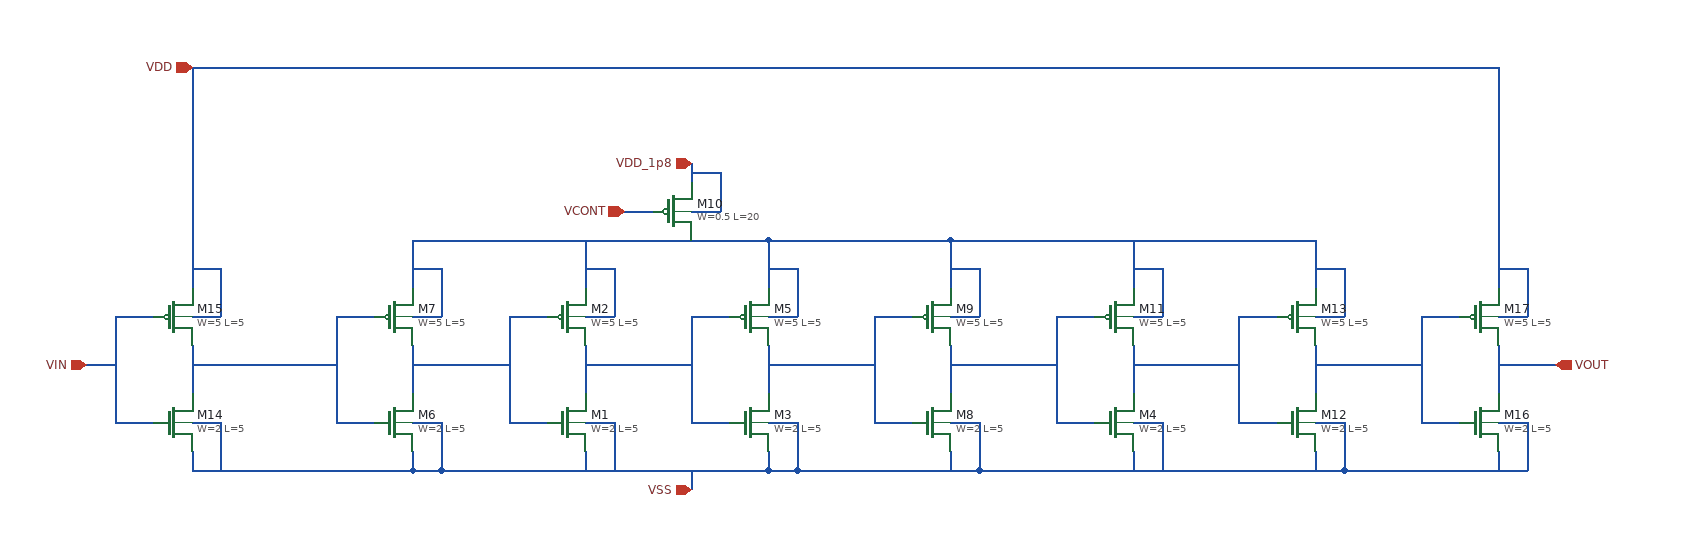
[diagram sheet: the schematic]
v {xschem version=3.4.5 file_version=1.2
}
G {}
K {}
V {}
S {}
E {}
N 170 20 210 20 { lab=#net1}
N 170 20 170 130 { lab=#net1}
N 170 130 210 130 { lab=#net1}
N 250 50 250 100 { lab=#net2}
N 250 -60 250 -10 { lab=#net3}
N 250 20 280 20 { lab=#net3}
N 280 -30 280 20 { lab=#net3}
N 250 130 280 130 { lab=VSS}
N 280 130 280 180 { lab=VSS}
N 250 160 250 180 { lab=VSS}
N 1200 70 1260 70 { lab=VOUT}
N 360 180 360 200 {
lab=VSS}
N 360 -140 360 -120 {
lab=VDD}
N 360 -90 390 -90 {
lab=VDD}
N 290 -90 320 -90 {
lab=VCONT}
N 250 180 280 180 {
lab=VSS}
N 250 -30 280 -30 {
lab=#net3}
N 390 -130 390 -90 {
lab=VDD}
N 360 -130 390 -130 {
lab=VDD}
N 360 20 400 20 { lab=#net2}
N 360 20 360 130 { lab=#net2}
N 360 130 400 130 { lab=#net2}
N 440 50 440 100 { lab=#net4}
N 440 -60 440 -10 { lab=#net3}
N 440 20 470 20 { lab=#net3}
N 470 -30 470 20 { lab=#net3}
N 440 130 470 130 { lab=VSS}
N 470 130 470 180 { lab=VSS}
N 440 160 440 180 { lab=VSS}
N 440 180 470 180 {
lab=VSS}
N 440 -30 470 -30 {
lab=#net3}
N -10 20 30 20 { lab=#net5}
N -10 20 -10 130 { lab=#net5}
N -10 130 30 130 { lab=#net5}
N 70 50 70 100 { lab=#net1}
N 70 -60 70 -10 { lab=#net3}
N 70 20 100 20 { lab=#net3}
N 100 -30 100 20 { lab=#net3}
N 70 130 100 130 { lab=VSS}
N 100 130 100 180 { lab=VSS}
N 70 160 70 180 { lab=VSS}
N 70 180 100 180 {
lab=VSS}
N 70 -30 100 -30 {
lab=#net3}
N 70 -60 440 -60 {
lab=#net3}
N 100 180 440 180 {
lab=VSS}
N -270 70 -240 70 {
lab=VIN}
N 70 70 170 70 {
lab=#net1}
N 250 70 360 70 {
lab=#net2}
N 550 20 590 20 { lab=#net4}
N 550 20 550 130 { lab=#net4}
N 550 130 590 130 { lab=#net4}
N 630 50 630 100 { lab=#net6}
N 630 -60 630 -10 { lab=#net3}
N 630 20 660 20 { lab=#net3}
N 660 -30 660 20 { lab=#net3}
N 630 130 660 130 { lab=VSS}
N 660 130 660 180 { lab=VSS}
N 440 70 550 70 {
lab=#net4}
N 440 -60 630 -60 {
lab=#net3}
N 630 -30 660 -30 {
lab=#net3}
N 470 180 660 180 {
lab=VSS}
N 630 160 630 180 {
lab=VSS}
N 740 20 780 20 { lab=#net6}
N 740 20 740 130 { lab=#net6}
N 740 130 780 130 { lab=#net6}
N 820 50 820 100 { lab=#net7}
N 820 20 850 20 { lab=#net3}
N 820 130 850 130 { lab=VSS}
N 850 130 850 180 { lab=VSS}
N 630 70 740 70 {
lab=#net6}
N 930 20 970 20 { lab=#net7}
N 930 20 930 130 { lab=#net7}
N 930 130 970 130 { lab=#net7}
N 1010 50 1010 100 { lab=#net8}
N 1010 20 1040 20 { lab=#net3}
N 1010 130 1040 130 { lab=VSS}
N 1040 130 1040 180 { lab=VSS}
N 820 70 930 70 {
lab=#net7}
N 660 180 1040 180 {
lab=VSS}
N 820 160 820 180 {
lab=VSS}
N 1010 160 1010 180 {
lab=VSS}
N 820 -60 820 -10 {
lab=#net3}
N 1010 -60 1010 -10 {
lab=#net3}
N 850 -30 850 20 {
lab=#net3}
N 820 -30 850 -30 {
lab=#net3}
N 1040 -30 1040 20 {
lab=#net3}
N 1010 -30 1040 -30 {
lab=#net3}
N 630 -60 1010 -60 {
lab=#net3}
N -240 20 -200 20 { lab=VIN}
N -240 20 -240 130 { lab=VIN}
N -240 130 -200 130 { lab=VIN}
N -160 50 -160 100 { lab=#net5}
N -160 20 -130 20 { lab=VDD}
N -130 -30 -130 20 { lab=VDD}
N -160 130 -130 130 { lab=VSS}
N -160 -30 -130 -30 {
lab=VDD}
N -110 70 -10 70 {
lab=#net5}
N -160 -60 -160 -10 {
lab=VDD}
N -160 70 -110 70 {
lab=#net5}
N -160 160 -160 180 {
lab=VSS}
N -160 180 70 180 {
lab=VSS}
N -130 130 -130 180 {
lab=VSS}
N -160 -140 -160 -60 {
lab=VDD}
N 1120 20 1160 20 { lab=#net8}
N 1120 20 1120 130 { lab=#net8}
N 1120 130 1160 130 { lab=#net8}
N 1200 50 1200 100 { lab=VOUT}
N 1200 20 1230 20 { lab=VDD}
N 1200 130 1230 130 { lab=VSS}
N 1230 130 1230 180 { lab=VSS}
N 1010 70 1120 70 {
lab=#net8}
N 1200 160 1200 180 {
lab=VSS}
N 1200 -60 1200 -10 {
lab=VDD}
N 1230 -30 1230 20 {
lab=VDD}
N 1200 -30 1230 -30 {
lab=VDD}
N 1040 180 1230 180 {
lab=VSS}
N 1200 -130 1200 -60 {
lab=VDD}
N -160 -240 -160 -140 {
lab=VDD}
N -160 -240 1200 -240 {
lab=VDD}
N 1200 -240 1200 -130 {
lab=VDD}
C {devices/ipin.sym} -270 70 0 0 {name=p1 lab=VIN}
C {devices/opin.sym} 1260 70 0 0 {name=p5 lab=VOUT}
C {devices/iopin.sym} 360 -140 3 0 {name=p2 lab=VDD_1p8}
C {devices/iopin.sym} 360 200 1 0 {name=p4 lab=VSS}
C {sky130_fd_pr/nfet_01v8.sym} 230 130 0 0 {name=M1
L=5
W=2
nf=1
mult=1
ad="'int((nf+1)/2) * W/nf * 0.29'" 
pd="'2*int((nf+1)/2) * (W/nf + 0.29)'"
as="'int((nf+2)/2) * W/nf * 0.29'" 
ps="'2*int((nf+2)/2) * (W/nf + 0.29)'"
nrd="'0.29 / W'" nrs="'0.29 / W'"
sa=0 sb=0 sd=0
model=nfet_01v8
spiceprefix=X
}
C {sky130_fd_pr/pfet_01v8.sym} 230 20 0 0 {name=M2
L=5
W=5
nf=1
mult=1
ad="'int((nf+1)/2) * W/nf * 0.29'" 
pd="'2*int((nf+1)/2) * (W/nf + 0.29)'"
as="'int((nf+2)/2) * W/nf * 0.29'" 
ps="'2*int((nf+2)/2) * (W/nf + 0.29)'"
nrd="'0.29 / W'" nrs="'0.29 / W'"
sa=0 sb=0 sd=0
model=pfet_01v8
spiceprefix=X
}
C {devices/ipin.sym} 290 -90 0 0 {name=p3 lab=VCONT}
C {sky130_fd_pr/nfet_01v8.sym} 420 130 0 0 {name=M3
L=5
W=2
nf=1
mult=1
ad="'int((nf+1)/2) * W/nf * 0.29'" 
pd="'2*int((nf+1)/2) * (W/nf + 0.29)'"
as="'int((nf+2)/2) * W/nf * 0.29'" 
ps="'2*int((nf+2)/2) * (W/nf + 0.29)'"
nrd="'0.29 / W'" nrs="'0.29 / W'"
sa=0 sb=0 sd=0
model=nfet_01v8
spiceprefix=X
}
C {sky130_fd_pr/pfet_01v8.sym} 420 20 0 0 {name=M5
L=5
W=5
nf=1
mult=1
ad="'int((nf+1)/2) * W/nf * 0.29'" 
pd="'2*int((nf+1)/2) * (W/nf + 0.29)'"
as="'int((nf+2)/2) * W/nf * 0.29'" 
ps="'2*int((nf+2)/2) * (W/nf + 0.29)'"
nrd="'0.29 / W'" nrs="'0.29 / W'"
sa=0 sb=0 sd=0
model=pfet_01v8
spiceprefix=X
}
C {sky130_fd_pr/nfet_01v8.sym} 50 130 0 0 {name=M6
L=5
W=2
nf=1
mult=1
ad="'int((nf+1)/2) * W/nf * 0.29'" 
pd="'2*int((nf+1)/2) * (W/nf + 0.29)'"
as="'int((nf+2)/2) * W/nf * 0.29'" 
ps="'2*int((nf+2)/2) * (W/nf + 0.29)'"
nrd="'0.29 / W'" nrs="'0.29 / W'"
sa=0 sb=0 sd=0
model=nfet_01v8
spiceprefix=X
}
C {sky130_fd_pr/pfet_01v8.sym} 50 20 0 0 {name=M7
L=5
W=5
nf=1
mult=1
ad="'int((nf+1)/2) * W/nf * 0.29'" 
pd="'2*int((nf+1)/2) * (W/nf + 0.29)'"
as="'int((nf+2)/2) * W/nf * 0.29'" 
ps="'2*int((nf+2)/2) * (W/nf + 0.29)'"
nrd="'0.29 / W'" nrs="'0.29 / W'"
sa=0 sb=0 sd=0
model=pfet_01v8
spiceprefix=X
}
C {sky130_fd_pr/nfet_01v8.sym} 610 130 0 0 {name=M8
L=5
W=2
nf=1
mult=1
ad="'int((nf+1)/2) * W/nf * 0.29'" 
pd="'2*int((nf+1)/2) * (W/nf + 0.29)'"
as="'int((nf+2)/2) * W/nf * 0.29'" 
ps="'2*int((nf+2)/2) * (W/nf + 0.29)'"
nrd="'0.29 / W'" nrs="'0.29 / W'"
sa=0 sb=0 sd=0
model=nfet_01v8
spiceprefix=X
}
C {sky130_fd_pr/pfet_01v8.sym} 610 20 0 0 {name=M9
L=5
W=5
nf=1
mult=1
ad="'int((nf+1)/2) * W/nf * 0.29'" 
pd="'2*int((nf+1)/2) * (W/nf + 0.29)'"
as="'int((nf+2)/2) * W/nf * 0.29'" 
ps="'2*int((nf+2)/2) * (W/nf + 0.29)'"
nrd="'0.29 / W'" nrs="'0.29 / W'"
sa=0 sb=0 sd=0
model=pfet_01v8
spiceprefix=X
}
C {sky130_fd_pr/pfet_01v8_lvt.sym} 340 -90 0 0 {name=M10
L=20
W=0.5
nf=1
mult=1
ad="'int((nf+1)/2) * W/nf * 0.29'" 
pd="'2*int((nf+1)/2) * (W/nf + 0.29)'"
as="'int((nf+2)/2) * W/nf * 0.29'" 
ps="'2*int((nf+2)/2) * (W/nf + 0.29)'"
nrd="'0.29 / W'" nrs="'0.29 / W'"
sa=0 sb=0 sd=0
model=pfet_01v8_lvt
spiceprefix=X
}
C {sky130_fd_pr/nfet_01v8.sym} 800 130 0 0 {name=M4
L=5
W=2
nf=1
mult=1
ad="'int((nf+1)/2) * W/nf * 0.29'" 
pd="'2*int((nf+1)/2) * (W/nf + 0.29)'"
as="'int((nf+2)/2) * W/nf * 0.29'" 
ps="'2*int((nf+2)/2) * (W/nf + 0.29)'"
nrd="'0.29 / W'" nrs="'0.29 / W'"
sa=0 sb=0 sd=0
model=nfet_01v8
spiceprefix=X
}
C {sky130_fd_pr/pfet_01v8.sym} 800 20 0 0 {name=M11
L=5
W=5
nf=1
mult=1
ad="'int((nf+1)/2) * W/nf * 0.29'" 
pd="'2*int((nf+1)/2) * (W/nf + 0.29)'"
as="'int((nf+2)/2) * W/nf * 0.29'" 
ps="'2*int((nf+2)/2) * (W/nf + 0.29)'"
nrd="'0.29 / W'" nrs="'0.29 / W'"
sa=0 sb=0 sd=0
model=pfet_01v8
spiceprefix=X
}
C {sky130_fd_pr/nfet_01v8.sym} 990 130 0 0 {name=M12
L=5
W=2
nf=1
mult=1
ad="'int((nf+1)/2) * W/nf * 0.29'" 
pd="'2*int((nf+1)/2) * (W/nf + 0.29)'"
as="'int((nf+2)/2) * W/nf * 0.29'" 
ps="'2*int((nf+2)/2) * (W/nf + 0.29)'"
nrd="'0.29 / W'" nrs="'0.29 / W'"
sa=0 sb=0 sd=0
model=nfet_01v8
spiceprefix=X
}
C {sky130_fd_pr/pfet_01v8.sym} 990 20 0 0 {name=M13
L=5
W=5
nf=1
mult=1
ad="'int((nf+1)/2) * W/nf * 0.29'" 
pd="'2*int((nf+1)/2) * (W/nf + 0.29)'"
as="'int((nf+2)/2) * W/nf * 0.29'" 
ps="'2*int((nf+2)/2) * (W/nf + 0.29)'"
nrd="'0.29 / W'" nrs="'0.29 / W'"
sa=0 sb=0 sd=0
model=pfet_01v8
spiceprefix=X
}
C {sky130_fd_pr/nfet_01v8.sym} -180 130 0 0 {name=M14
L=5
W=2
nf=1
mult=1
ad="'int((nf+1)/2) * W/nf * 0.29'" 
pd="'2*int((nf+1)/2) * (W/nf + 0.29)'"
as="'int((nf+2)/2) * W/nf * 0.29'" 
ps="'2*int((nf+2)/2) * (W/nf + 0.29)'"
nrd="'0.29 / W'" nrs="'0.29 / W'"
sa=0 sb=0 sd=0
model=nfet_01v8
spiceprefix=X
}
C {sky130_fd_pr/pfet_01v8.sym} -180 20 0 0 {name=M15
L=5
W=5
nf=1
mult=1
ad="'int((nf+1)/2) * W/nf * 0.29'" 
pd="'2*int((nf+1)/2) * (W/nf + 0.29)'"
as="'int((nf+2)/2) * W/nf * 0.29'" 
ps="'2*int((nf+2)/2) * (W/nf + 0.29)'"
nrd="'0.29 / W'" nrs="'0.29 / W'"
sa=0 sb=0 sd=0
model=pfet_01v8
spiceprefix=X
}
C {sky130_fd_pr/nfet_01v8.sym} 1180 130 0 0 {name=M16
L=5
W=2
nf=1
mult=1
ad="'int((nf+1)/2) * W/nf * 0.29'" 
pd="'2*int((nf+1)/2) * (W/nf + 0.29)'"
as="'int((nf+2)/2) * W/nf * 0.29'" 
ps="'2*int((nf+2)/2) * (W/nf + 0.29)'"
nrd="'0.29 / W'" nrs="'0.29 / W'"
sa=0 sb=0 sd=0
model=nfet_01v8
spiceprefix=X
}
C {sky130_fd_pr/pfet_01v8.sym} 1180 20 0 0 {name=M17
L=5
W=5
nf=1
mult=1
ad="'int((nf+1)/2) * W/nf * 0.29'" 
pd="'2*int((nf+1)/2) * (W/nf + 0.29)'"
as="'int((nf+2)/2) * W/nf * 0.29'" 
ps="'2*int((nf+2)/2) * (W/nf + 0.29)'"
nrd="'0.29 / W'" nrs="'0.29 / W'"
sa=0 sb=0 sd=0
model=pfet_01v8
spiceprefix=X
}
C {devices/iopin.sym} -160 -240 3 0 {name=p6 lab=VDD}
